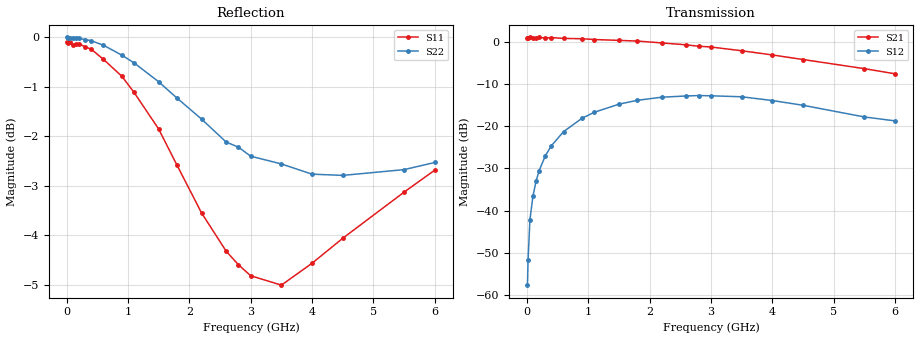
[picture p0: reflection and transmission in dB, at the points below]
! SIEMENS Small Signal Semiconductors
! BFP181
! Si NPN RF Bipolar Junction Transistor in SOT143
! VCE = 2 V  IC = 0.3 mA
! Common Emitter S-Parameters:  March  1996
# GHz  S  MA  R  50
!  f  S11  S21  S12  S22
! GHz  MAG  ANG  MAG  ANG  MAG  ANG  MAG  ANG
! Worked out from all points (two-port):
!   36 points, 10 MHz to 6 GHz, reference 50 ohm
!   highest |S21| = 1.16 dB at 50 MHz (marker M1); lowest = -7.5 dB at 6 GHz (marker M2)
!   |S21| within 3 dB of the highest: start of sweep to 3.402 GHz
!   lowest |S11| = -5.0 dB at 3.5 GHz (marker M3), VSWR 3.57, Z = 14.2 + j5.73 ohm
!   |S11| at or under -10 dB: nowhere
!   |S22| runs from -2.8 to 0.0 dB; largest |S21 - S12| = 1.1
!   S11 on the Smith chart (normalised r, x): 10 MHz: open; 900 MHz: 0.31, -2.41; 1.8 GHz: 0.28, -0.93; 2.8 GHz: 0.27, -0.23; 4 GHz: 0.28, +0.32; 6 GHz: 0.31, +0.98
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0.01  0.9879 -0.5  1.119 180.0  0.0013 96.3  0.9996 -0.2
0.02  0.9857 -0.9  1.127 179.7  0.0026 95.1  0.9993 -0.5
0.05  0.9884 -2.3  1.143 177.5  0.0078 90.2  0.999 -1.2
0.1  0.9818 -4.9  1.123 174.8  0.0149 86.7  0.9988 -2.4
0.15  0.9838 -7.3  1.134 172.5  0.0223 84.1  0.9986 -3.6
0.2  0.9847 -9.7  1.143 169.6  0.0298 83.1  0.9972 -5.0
0.3  0.978 -14.8  1.125 165.2  0.0446 79.0  0.9946 -7.4
0.4  0.9726 -19.7  1.137 159.2  0.059 75.6  0.9919 -9.8
0.6  0.9499 -29.4  1.112 149.2  0.0869 68.0  0.9816 -14.6
0.9  0.9132 -44.5  1.101 134.5  0.1251 57.1  0.9591 -21.7
1.1  0.8794 -54.6  1.078 124.9  0.1473 50.3  0.942 -26.2
1.5  0.8078 -75.3  1.053 106.9  0.1837 37.3  0.9016 -34.6
1.8  0.7424 -91.9  1.034 93.1  0.2042 28.5  0.8679 -40.3
2.2  0.6645 -115.0  0.982 75.8  0.2225 17.0  0.8266 -47.7
2.6  0.6081 -139.7  0.932 60.4  0.23 6.8  0.7837 -54.3
2.8  0.5892 -151.9  0.897 52.2  0.2328 1.5  0.7744 -57.6
3  0.5743 -164.7  0.879 44.7  0.2312 -3.6  0.7583 -61.1
3.5  0.5619 165.8  0.793 27.3  0.2251 -14.3  0.7448 -69.3
4  0.5912 142.2  0.707 12.2  0.2031 -23.5  0.7273 -78.9
4.5  0.6265 123.2  0.624 -1.0  0.1784 -30.6  0.7252 -89.5
5.5  0.6975 97.6  0.486 -20.5  0.1296 -32.3  0.735 -111.6
6  0.7341 88.3  0.422 -27.8  0.1164 -27.3  0.7473 -123.0
